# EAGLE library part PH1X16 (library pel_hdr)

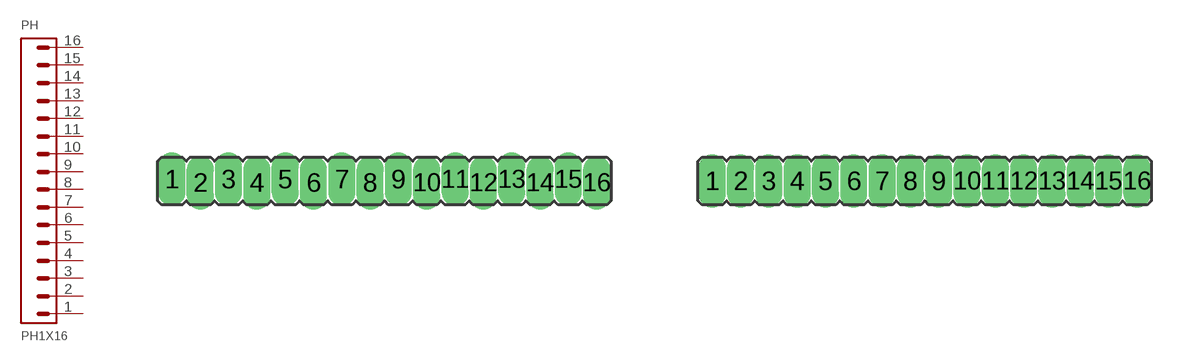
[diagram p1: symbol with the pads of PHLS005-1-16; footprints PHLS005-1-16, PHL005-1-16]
Designator prefix PH

## PH1X16-05LONGSNAP  [PHLS005-1-16]
1  1
2  2
3  3
4  4
5  5
6  6
7  7
8  8
9  9
10  10
11  11
12  12
13  13
14  14
15  15
16  16

## PH1X16-05LONG  [PHL005-1-16]
Pads as for PHLS005-1-16

## PH1X16-05LONGCLEAN  [PHLC005-1-16]
Pads as for PHLS005-1-16

## Footprint PHLS005-1-16 (pad centres in mm)
drill 0.7 pad 1.016 long: 1 0,0.076; 2 1.27,-0.076; 3 2.54,0.076; 4 3.81,-0.076; 5 5.08,0.076; 6 6.35,-0.076; 7 7.62,0.076; 8 8.89,-0.076; 9 10.16,0.076; 10 11.43,-0.076; 11 12.7,0.076; 12 13.97,-0.076; 13 15.24,0.076; 14 16.51,-0.076; 15 17.78,0.076; 16 19.05,-0.076

## Footprint PHL005-1-16 (pad centres in mm)
drill 0.7 pad 1.016 long: 1 0,0; 2 1.27,0; 3 2.54,0; 4 3.81,0; 5 5.08,0; 6 6.35,0; 7 7.62,0; 8 8.89,0; 9 10.16,0; 10 11.43,0; 11 12.7,0; 12 13.97,0; 13 15.24,0; 14 16.51,0; 15 17.78,0; 16 19.05,0

## Footprint PHLC005-1-16 (pad centres in mm)
drill 0.7 pad 1.016 long: 1 0,0; 2 1.27,0; 3 2.54,0; 4 3.81,0; 5 5.08,0; 6 6.35,0; 7 7.62,0; 8 8.89,0; 9 10.16,0; 10 11.43,0; 11 12.7,0; 12 13.97,0; 13 15.24,0; 14 16.51,0; 15 17.78,0; 16 19.05,0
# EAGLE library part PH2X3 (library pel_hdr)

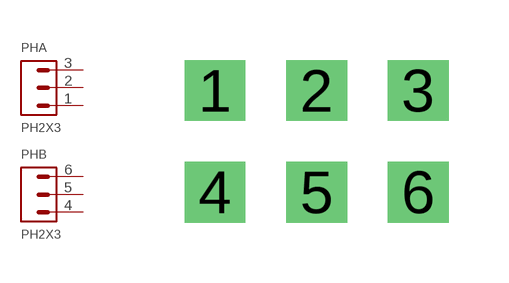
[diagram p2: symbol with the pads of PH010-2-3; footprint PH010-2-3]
Designator prefix PH; gates A=PH1X3 B=PH1X3

## PH2X3  [PH010-2-3]
1  A:1
2  A:2
3  A:3
4  B:1
5  B:2
6  B:3

## Footprint PH010-2-3 (pad centres in mm)
drill 1.016 square: 1 0,0; 2 2.54,0; 3 5.08,0; 4 0,-2.54; 5 2.54,-2.54; 6 5.08,-2.54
